VERSION 5.8 ;
BUSBITCHARS "[]" ;
DIVIDERCHAR "/" ;
UNITS
    DATABASE MICRONS 1000 ;
END UNITS

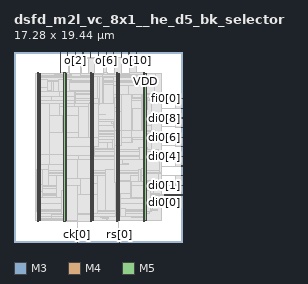
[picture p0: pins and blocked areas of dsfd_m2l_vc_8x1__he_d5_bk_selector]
MACRO dsfd_m2l_vc_8x1__he_d5_bk_selector
  FOREIGN dsfd_m2l_vc_8x1__he_d5_bk_selector 0 0 ;
  CLASS BLOCK ;
  SIZE 17.28 BY 19.44 ;
  PIN ck[0]
    DIRECTION INPUT ;
    USE SIGNAL ;
    PORT
      LAYER M3 ;
        RECT  6.48 0 6.498 0.144 ;
    END
    PORT
      LAYER M3 ;
        RECT  6.48 0.108 6.498 0.173 ;
    END
  END ck[0]
  PIN di0[0]
    DIRECTION INPUT ;
    USE SIGNAL ;
    PORT
      LAYER M4 ;
        RECT  17.088 4.8 17.28 4.824 ;
    END
    PORT
      LAYER M4 ;
        RECT  15.397 4.8 17.1 4.824 ;
    END
  END di0[0]
  PIN di0[1]
    DIRECTION INPUT ;
    USE SIGNAL ;
    PORT
      LAYER M4 ;
        RECT  17.088 5.808 17.28 5.832 ;
    END
  END di0[1]
  PIN di0[2]
    DIRECTION INPUT ;
    USE SIGNAL ;
    PORT
      LAYER M4 ;
        RECT  17.088 6.768 17.28 6.792 ;
    END
  END di0[2]
  PIN di0[3]
    DIRECTION INPUT ;
    USE SIGNAL ;
    PORT
      LAYER M4 ;
        RECT  17.088 7.776 17.28 7.8 ;
    END
  END di0[3]
  PIN di0[4]
    DIRECTION INPUT ;
    USE SIGNAL ;
    PORT
      LAYER M4 ;
        RECT  17.088 8.736 17.28 8.76 ;
    END
  END di0[4]
  PIN di0[5]
    DIRECTION INPUT ;
    USE SIGNAL ;
    PORT
      LAYER M4 ;
        RECT  17.088 9.744 17.28 9.768 ;
    END
  END di0[5]
  PIN di0[6]
    DIRECTION INPUT ;
    USE SIGNAL ;
    PORT
      LAYER M4 ;
        RECT  17.088 10.704 17.28 10.728 ;
    END
  END di0[6]
  PIN di0[7]
    DIRECTION INPUT ;
    USE SIGNAL ;
    PORT
      LAYER M4 ;
        RECT  17.088 11.712 17.28 11.736 ;
    END
  END di0[7]
  PIN di0[8]
    DIRECTION INPUT ;
    USE SIGNAL ;
    PORT
      LAYER M4 ;
        RECT  17.088 12.672 17.28 12.696 ;
    END
  END di0[8]
  PIN di0[9]
    DIRECTION INPUT ;
    USE SIGNAL ;
    PORT
      LAYER M4 ;
        RECT  17.088 13.68 17.28 13.704 ;
    END
  END di0[9]
  PIN fi0[0]
    DIRECTION INPUT ;
    USE SIGNAL ;
    PORT
      LAYER M4 ;
        RECT  17.088 14.64 17.28 14.664 ;
    END
  END fi0[0]
  PIN o[0]
    DIRECTION OUTPUT ;
    USE SIGNAL ;
    PORT
      LAYER M3 ;
        RECT  4.716 19.296 4.734 19.44 ;
    END
    PORT
      LAYER M3 ;
        RECT  4.716 17.297 4.734 19.308 ;
    END
  END o[0]
  PIN o[10]
    DIRECTION OUTPUT ;
    USE SIGNAL ;
    PORT
      LAYER M3 ;
        RECT  12.564 19.296 12.582 19.44 ;
    END
    PORT
      LAYER M3 ;
        RECT  12.564 18.845 12.582 19.308 ;
    END
  END o[10]
  PIN o[1]
    DIRECTION OUTPUT ;
    USE SIGNAL ;
    PORT
      LAYER M5 ;
        RECT  5.472 19.248 5.496 19.44 ;
    END
    PORT
      LAYER M5 ;
        RECT  5.472 18.805 5.496 19.28 ;
    END
  END o[1]
  PIN o[2]
    DIRECTION OUTPUT ;
    USE SIGNAL ;
    PORT
      LAYER M3 ;
        RECT  6.264 19.296 6.282 19.44 ;
    END
    PORT
      LAYER M3 ;
        RECT  6.264 18.845 6.282 19.308 ;
    END
  END o[2]
  PIN o[3]
    DIRECTION OUTPUT ;
    USE SIGNAL ;
    PORT
      LAYER M5 ;
        RECT  7.056 19.248 7.08 19.44 ;
    END
    PORT
      LAYER M5 ;
        RECT  7.056 18.805 7.08 19.28 ;
    END
  END o[3]
  PIN o[4]
    DIRECTION OUTPUT ;
    USE SIGNAL ;
    PORT
      LAYER M3 ;
        RECT  7.848 19.296 7.866 19.44 ;
    END
    PORT
      LAYER M3 ;
        RECT  7.848 18.845 7.866 19.308 ;
    END
  END o[4]
  PIN o[5]
    DIRECTION OUTPUT ;
    USE SIGNAL ;
    PORT
      LAYER M5 ;
        RECT  8.64 19.248 8.664 19.44 ;
    END
    PORT
      LAYER M5 ;
        RECT  8.64 18.805 8.664 19.28 ;
    END
  END o[5]
  PIN o[6]
    DIRECTION OUTPUT ;
    USE SIGNAL ;
    PORT
      LAYER M3 ;
        RECT  9.432 19.296 9.45 19.44 ;
    END
    PORT
      LAYER M3 ;
        RECT  9.432 18.845 9.45 19.308 ;
    END
  END o[6]
  PIN o[7]
    DIRECTION OUTPUT ;
    USE SIGNAL ;
    PORT
      LAYER M5 ;
        RECT  10.176 19.248 10.2 19.44 ;
    END
    PORT
      LAYER M5 ;
        RECT  10.176 18.805 10.2 19.28 ;
    END
  END o[7]
  PIN o[8]
    DIRECTION OUTPUT ;
    USE SIGNAL ;
    PORT
      LAYER M3 ;
        RECT  10.98 19.296 10.998 19.44 ;
    END
    PORT
      LAYER M3 ;
        RECT  10.98 18.845 10.998 19.308 ;
    END
  END o[8]
  PIN o[9]
    DIRECTION OUTPUT ;
    USE SIGNAL ;
    PORT
      LAYER M5 ;
        RECT  11.76 19.248 11.784 19.44 ;
    END
    PORT
      LAYER M5 ;
        RECT  11.76 18.805 11.784 19.28 ;
    END
  END o[9]
  PIN rs[0]
    DIRECTION INPUT ;
    USE SIGNAL ;
    PORT
      LAYER M5 ;
        RECT  10.8 0 10.824 0.192 ;
    END
    PORT
      LAYER M5 ;
        RECT  10.8 0.144 10.824 0.227 ;
    END
  END rs[0]
  PIN VDD
    DIRECTION INOUT ;
    USE POWER ;
    PORT
      LAYER M5 ;
        RECT  13.392 2.151 13.512 17.289 ;
        RECT  10.692 2.151 10.812 17.289 ;
        RECT  7.992 2.151 8.112 17.289 ;
        RECT  5.292 2.151 5.412 17.289 ;
        RECT  2.592 2.151 2.712 17.289 ;
    END
  END VDD
  PIN VSS
    DIRECTION INOUT ;
    USE GROUND ;
    PORT
      LAYER M5 ;
        RECT  13.2 2.137 13.32 17.303 ;
        RECT  10.5 2.137 10.62 17.303 ;
        RECT  7.8 2.137 7.92 17.303 ;
        RECT  5.1 2.137 5.22 17.303 ;
        RECT  2.4 2.137 2.52 17.303 ;
    END
  END VSS
  # OT_OBS_CLOSED layer=M5 d_um=1.536 added=29
  OBS
    LAYER RVTN ;
     RECT  2.16 2.16 15.12 2.295 ;
     RECT  2.16 2.565 15.12 2.835 ;
     RECT  2.16 3.105 15.12 3.375 ;
     RECT  2.16 3.645 15.12 3.915 ;
     RECT  2.16 4.185 15.12 4.455 ;
     RECT  2.16 4.725 15.12 4.995 ;
     RECT  2.16 5.265 15.12 5.535 ;
     RECT  2.16 5.805 15.12 6.075 ;
     RECT  2.16 6.345 15.12 6.615 ;
     RECT  2.16 6.885 15.12 7.155 ;
     RECT  2.16 7.425 15.12 7.695 ;
     RECT  2.16 7.965 15.12 8.235 ;
     RECT  2.16 8.505 15.12 8.775 ;
     RECT  2.16 9.045 15.12 9.315 ;
     RECT  2.16 9.585 15.12 9.855 ;
     RECT  2.16 10.125 15.12 10.395 ;
     RECT  2.16 10.665 15.12 10.935 ;
     RECT  2.16 11.205 15.12 11.475 ;
     RECT  2.16 11.745 15.12 12.015 ;
     RECT  2.16 12.285 15.12 12.555 ;
     RECT  2.16 12.825 15.12 13.095 ;
     RECT  2.16 13.365 15.12 13.635 ;
     RECT  2.16 13.905 15.12 14.175 ;
     RECT  2.16 14.445 15.12 14.715 ;
     RECT  2.16 14.985 15.12 15.255 ;
     RECT  2.16 15.525 15.12 15.795 ;
     RECT  2.16 16.065 15.12 16.335 ;
     RECT  2.16 16.605 15.12 16.875 ;
     RECT  2.16 17.145 15.12 17.28 ;
    LAYER RVTP ;
     RECT  2.16 2.295 15.12 2.565 ;
     RECT  2.16 2.835 15.12 3.105 ;
     RECT  2.16 3.375 15.12 3.645 ;
     RECT  2.16 3.915 15.12 4.185 ;
     RECT  2.16 4.455 15.12 4.725 ;
     RECT  2.16 4.995 15.12 5.265 ;
     RECT  2.16 5.535 15.12 5.805 ;
     RECT  2.16 6.075 15.12 6.345 ;
     RECT  2.16 6.615 15.12 6.885 ;
     RECT  2.16 7.155 15.12 7.425 ;
     RECT  2.16 7.695 15.12 7.965 ;
     RECT  2.16 8.235 15.12 8.505 ;
     RECT  2.16 8.775 15.12 9.045 ;
     RECT  2.16 9.315 15.12 9.585 ;
     RECT  2.16 9.855 15.12 10.125 ;
     RECT  2.16 10.395 15.12 10.665 ;
     RECT  2.16 10.935 15.12 11.205 ;
     RECT  2.16 11.475 15.12 11.745 ;
     RECT  2.16 12.015 15.12 12.285 ;
     RECT  2.16 12.555 15.12 12.825 ;
     RECT  2.16 13.095 15.12 13.365 ;
     RECT  2.16 13.635 15.12 13.905 ;
     RECT  2.16 14.175 15.12 14.445 ;
     RECT  2.16 14.715 15.12 14.985 ;
     RECT  2.16 15.255 15.12 15.525 ;
     RECT  2.16 15.795 15.12 16.065 ;
     RECT  2.16 16.335 15.12 16.605 ;
     RECT  2.16 16.875 15.12 17.145 ;
    LAYER M1 ;
     RECT  2.16 2.151 15.12 17.289 ;
    LAYER M2 ;
     RECT  6.259 18.81 6.863 18.828 ;
     RECT  7.663 18.774 7.871 18.792 ;
     RECT  2.16 2.151 9.427 17.289 ;
     RECT  9.427 2.151 9.527 17.334 ;
     RECT  9.527 2.151 15.12 17.289 ;
     RECT  15.12 4.77 15.431 4.788 ;
     RECT  15.12 6.048 15.431 6.066 ;
     RECT  15.12 6.822 16.547 6.84 ;
     RECT  15.12 7.704 16.547 7.722 ;
     RECT  15.12 8.784 16.547 8.802 ;
     RECT  15.12 9.9 16.547 9.918 ;
     RECT  15.12 10.872 16.547 10.89 ;
     RECT  15.12 11.79 16.547 11.808 ;
     RECT  15.12 12.87 16.547 12.888 ;
     RECT  15.12 13.644 16.547 13.662 ;
    LAYER M3 ;
     RECT  10.656 0.187 10.674 2.143 ;
     RECT  2.415 2.143 2.505 2.191 ;
     RECT  5.115 2.143 5.205 2.191 ;
     RECT  2.415 2.191 2.898 2.263 ;
     RECT  2.415 2.263 3.366 2.335 ;
     RECT  2.415 2.335 3.618 2.347 ;
     RECT  4.5 2.191 5.205 2.347 ;
     RECT  2.415 2.347 5.205 2.371 ;
     RECT  2.415 2.371 5.274 2.413 ;
     RECT  7.815 2.143 7.905 2.413 ;
     RECT  10.515 2.143 10.674 2.413 ;
     RECT  13.215 2.143 13.305 2.413 ;
     RECT  13.215 2.413 13.497 2.461 ;
     RECT  9.036 2.371 9.702 2.497 ;
     RECT  8.82 2.497 9.702 2.587 ;
     RECT  10.515 2.413 10.797 2.587 ;
     RECT  11.988 2.461 13.497 2.587 ;
     RECT  2.415 2.413 5.397 2.605 ;
     RECT  6.228 2.569 6.246 2.605 ;
     RECT  2.415 2.605 6.75 2.641 ;
     RECT  7.815 2.413 8.097 2.641 ;
     RECT  8.82 2.587 13.497 2.641 ;
     RECT  2.415 2.641 13.497 2.911 ;
     RECT  2.415 2.911 13.842 3.145 ;
     RECT  2.34 3.145 14.022 3.181 ;
     RECT  2.34 3.181 14.67 3.335 ;
     RECT  2.34 3.335 14.13 3.983 ;
     RECT  2.415 3.983 14.13 4.531 ;
     RECT  2.415 4.531 14.85 4.765 ;
     RECT  2.415 4.765 15.426 4.829 ;
     RECT  2.415 4.829 14.85 4.955 ;
     RECT  2.415 4.955 14.238 5.461 ;
     RECT  2.412 5.461 14.238 5.701 ;
     RECT  2.412 5.701 14.742 5.803 ;
     RECT  2.412 5.803 15.426 6.071 ;
     RECT  2.412 6.071 14.742 6.235 ;
     RECT  2.376 6.235 14.742 6.275 ;
     RECT  16.524 6.763 16.542 6.845 ;
     RECT  2.415 6.275 14.742 6.961 ;
     RECT  2.415 6.961 14.994 7.079 ;
     RECT  2.415 7.079 14.85 7.339 ;
     RECT  2.412 7.339 14.85 7.357 ;
     RECT  16.524 7.699 16.542 7.805 ;
     RECT  2.376 7.357 14.85 8.429 ;
     RECT  2.415 8.429 14.85 8.707 ;
     RECT  2.415 8.707 14.886 8.807 ;
     RECT  16.524 8.731 16.542 8.807 ;
     RECT  2.415 8.807 14.778 9.259 ;
     RECT  2.376 9.259 14.778 9.509 ;
     RECT  16.524 9.739 16.542 9.923 ;
     RECT  2.415 9.509 14.094 10.471 ;
     RECT  2.415 10.471 14.346 10.831 ;
     RECT  16.524 10.699 16.542 10.895 ;
     RECT  2.415 10.831 14.526 11.011 ;
     RECT  2.415 11.011 14.994 11.129 ;
     RECT  2.415 11.129 14.562 11.357 ;
     RECT  2.415 11.357 14.526 11.399 ;
     RECT  2.415 11.399 14.418 11.435 ;
     RECT  2.415 11.435 14.094 11.443 ;
     RECT  16.524 11.707 16.542 11.813 ;
     RECT  2.376 11.443 14.094 11.939 ;
     RECT  2.415 11.939 14.094 12.361 ;
     RECT  2.415 12.361 14.13 12.515 ;
     RECT  16.524 12.667 16.542 12.893 ;
     RECT  16.524 13.639 16.542 13.709 ;
     RECT  2.415 12.515 14.094 14.521 ;
     RECT  2.415 14.521 14.778 14.675 ;
     RECT  2.415 14.675 14.526 15.061 ;
     RECT  2.376 15.061 14.526 15.179 ;
     RECT  2.376 15.179 14.418 15.215 ;
     RECT  2.376 15.215 14.346 16.339 ;
     RECT  2.376 16.339 14.526 16.375 ;
     RECT  2.376 16.375 14.634 16.529 ;
     RECT  2.415 16.529 14.526 16.799 ;
     RECT  2.415 16.799 13.497 16.943 ;
     RECT  2.415 16.943 5.922 17.027 ;
     RECT  9.108 16.943 13.497 17.027 ;
     RECT  3.348 17.027 5.922 17.069 ;
     RECT  6.84 16.943 8.298 17.069 ;
     RECT  9.108 17.027 13.305 17.069 ;
     RECT  14.436 16.799 14.526 17.069 ;
     RECT  4.176 17.069 5.922 17.105 ;
     RECT  10.332 17.069 13.305 17.105 ;
     RECT  14.436 17.069 14.454 17.105 ;
     RECT  4.284 17.105 5.634 17.141 ;
     RECT  6.84 17.069 8.19 17.213 ;
     RECT  2.415 17.027 2.505 17.297 ;
     RECT  4.716 17.141 5.634 17.297 ;
     RECT  11.844 17.105 13.305 17.297 ;
     RECT  9.108 17.069 9.522 17.339 ;
     RECT  7.668 17.213 8.19 18.797 ;
     RECT  5.616 17.297 5.634 18.805 ;
     RECT  6.84 17.213 6.858 18.805 ;
     RECT  5.616 18.805 6.858 18.833 ;
     RECT  5.616 18.833 6.282 18.845 ;
     RECT  7.848 18.797 8.19 18.845 ;
     RECT  9.108 17.339 9.45 18.845 ;
     RECT  10.332 17.105 10.998 18.845 ;
     RECT  11.844 17.297 12.582 18.845 ;
    LAYER M4 ;
     RECT  2.293 7.344 2.365 7.368 ;
     RECT  2.293 6.24 2.401 6.264 ;
     RECT  2.293 3.936 2.408 3.96 ;
     RECT  2.401 5.472 2.408 6.264 ;
     RECT  2.365 7.344 2.408 7.944 ;
     RECT  2.365 9.264 2.408 9.288 ;
     RECT  2.365 16.032 2.408 16.056 ;
     RECT  2.408 2.148 2.512 17.292 ;
     RECT  2.512 2.4 2.704 17.022 ;
     RECT  2.704 4.512 2.915 9.288 ;
     RECT  2.704 15.456 3.443 16.584 ;
     RECT  2.704 13.872 3.449 14.424 ;
     RECT  2.915 5.808 3.491 9.288 ;
     RECT  2.704 2.4 3.589 2.424 ;
     RECT  3.491 7.92 3.635 9.192 ;
     RECT  3.449 14.208 3.797 14.424 ;
     RECT  3.443 15.456 3.797 16.392 ;
     RECT  3.589 2.352 3.805 2.424 ;
     RECT  3.805 2.352 3.845 2.808 ;
     RECT  3.797 14.208 3.875 16.392 ;
     RECT  3.875 14.352 4.061 16.392 ;
     RECT  3.913 13.008 4.097 13.128 ;
     RECT  4.097 13.008 4.133 13.032 ;
     RECT  2.915 4.512 4.381 4.536 ;
     RECT  3.491 5.808 4.381 6.84 ;
     RECT  4.061 14.4 4.525 16.392 ;
     RECT  2.704 11.376 4.645 11.976 ;
     RECT  3.635 8.208 4.741 9.192 ;
     RECT  4.645 11.376 4.777 12.936 ;
     RECT  3.845 2.784 4.885 2.808 ;
     RECT  4.885 2.784 5.108 2.904 ;
     RECT  4.381 4.512 5.108 6.84 ;
     RECT  4.741 8.16 5.108 9.192 ;
     RECT  4.777 10.944 5.108 12.936 ;
     RECT  4.525 14.4 5.108 16.584 ;
     RECT  5.108 2.148 5.212 17.292 ;
     RECT  5.212 2.418 5.404 17.022 ;
     RECT  5.461 18.816 5.645 18.84 ;
     RECT  5.404 2.784 5.681 2.808 ;
     RECT  5.404 14.112 5.681 16.584 ;
     RECT  5.681 16.56 5.933 16.584 ;
     RECT  5.681 14.112 6.329 15.48 ;
     RECT  5.404 5.136 6.397 11.256 ;
     RECT  5.404 12.24 6.397 13.128 ;
     RECT  6.428 0.144 6.515 0.168 ;
     RECT  6.397 5.136 6.541 13.128 ;
     RECT  6.329 14.112 6.541 14.136 ;
     RECT  6.541 5.136 6.721 14.136 ;
     RECT  6.721 2.832 6.805 2.856 ;
     RECT  6.721 4.848 7.693 14.136 ;
     RECT  6.805 2.832 7.765 3.576 ;
     RECT  7.693 4.848 7.765 14.232 ;
     RECT  6.329 15.36 7.801 15.48 ;
     RECT  7.765 2.832 7.808 14.232 ;
     RECT  7.801 15.36 7.808 15.528 ;
     RECT  6.829 17.04 7.808 17.064 ;
     RECT  7.808 2.148 7.912 17.292 ;
     RECT  7.912 2.418 8.104 17.022 ;
     RECT  8.104 8.832 8.243 10.584 ;
     RECT  8.104 11.664 8.243 17.022 ;
     RECT  8.243 12.24 8.245 17.022 ;
     RECT  8.243 9.6 8.281 10.584 ;
     RECT  8.104 2.88 8.531 6.792 ;
     RECT  8.245 12.24 8.597 13.08 ;
     RECT  8.245 14.112 8.705 17.022 ;
     RECT  8.705 14.208 9.061 17.022 ;
     RECT  9.061 14.208 9.107 17.112 ;
     RECT  7.045 18.816 9.137 18.84 ;
     RECT  9.107 17.088 9.245 17.112 ;
     RECT  8.597 13.056 9.317 13.08 ;
     RECT  8.531 3.264 9.385 6.792 ;
     RECT  8.281 9.6 9.565 10.2 ;
     RECT  9.925 12.288 9.961 12.312 ;
     RECT  9.565 9.552 10.069 10.2 ;
     RECT  9.961 12.144 10.141 12.312 ;
     RECT  9.107 14.208 10.172 16.104 ;
     RECT  10.141 12.096 10.177 12.312 ;
     RECT  10.172 14.208 10.241 16.392 ;
     RECT  9.385 3.264 10.357 7.368 ;
     RECT  9.097 8.448 10.357 8.472 ;
     RECT  10.165 18.816 10.361 18.84 ;
     RECT  10.357 2.592 10.508 8.472 ;
     RECT  10.069 9.552 10.508 10.44 ;
     RECT  10.177 11.76 10.508 12.312 ;
     RECT  10.241 13.68 10.508 16.392 ;
     RECT  10.508 2.148 10.612 17.292 ;
     RECT  10.612 2.418 10.804 17.022 ;
     RECT  10.645 0.192 10.835 0.216 ;
     RECT  10.804 2.592 10.931 6.312 ;
     RECT  10.804 9.888 10.979 16.008 ;
     RECT  10.804 7.968 11.081 8.472 ;
     RECT  10.931 4.416 11.117 6.312 ;
     RECT  10.931 2.592 11.441 3.384 ;
     RECT  11.081 7.968 11.765 7.992 ;
     RECT  11.749 18.816 11.873 18.84 ;
     RECT  11.117 4.512 11.905 6.312 ;
     RECT  11.905 4.512 11.945 6.84 ;
     RECT  11.945 4.512 11.987 4.584 ;
     RECT  11.441 2.592 12.017 2.616 ;
     RECT  10.979 10.224 12.053 16.008 ;
     RECT  12.053 14.736 12.085 16.008 ;
     RECT  12.053 10.224 12.089 13.656 ;
     RECT  11.945 5.712 12.733 6.84 ;
     RECT  12.733 8.448 12.805 8.472 ;
     RECT  12.769 9.6 12.805 9.624 ;
     RECT  11.987 4.56 12.913 4.584 ;
     RECT  12.733 5.712 12.913 7.464 ;
     RECT  12.085 14.736 13.057 16.056 ;
     RECT  12.089 10.752 13.093 13.656 ;
     RECT  13.057 14.64 13.093 16.056 ;
     RECT  13.093 10.752 13.165 16.056 ;
     RECT  12.913 4.56 13.208 7.464 ;
     RECT  12.805 8.448 13.208 9.624 ;
     RECT  13.165 10.752 13.208 16.44 ;
     RECT  13.208 2.148 13.312 17.292 ;
     RECT  13.312 2.418 13.504 17.022 ;
     RECT  13.504 13.104 13.565 14.76 ;
     RECT  13.504 4.512 13.601 6.84 ;
     RECT  13.504 16.032 13.637 16.056 ;
     RECT  13.504 9.6 13.673 9.624 ;
     RECT  13.504 8.448 13.709 8.472 ;
     RECT  13.565 13.584 13.709 14.76 ;
     RECT  13.709 14.496 13.853 14.76 ;
     RECT  13.853 14.496 13.961 14.664 ;
     RECT  13.601 4.512 14.003 6.072 ;
     RECT  13.504 3.168 14.044 3.192 ;
     RECT  14.003 4.512 14.044 4.536 ;
     RECT  14.003 6.048 14.069 6.072 ;
     RECT  13.504 11.328 14.573 11.352 ;
     RECT  15.397 5.808 16.513 5.832 ;
     RECT  13.961 14.64 16.513 14.664 ;
     RECT  16.513 5.808 17.1 6.792 ;
     RECT  16.513 7.776 17.1 8.76 ;
     RECT  16.513 9.744 17.1 10.728 ;
     RECT  16.513 11.712 17.1 12.696 ;
     RECT  16.513 13.68 17.1 14.664 ;
    LAYER M5 ;
     RECT  2.4 2.137 2.52 2.151 ;
     RECT  5.1 2.137 5.22 2.151 ;
     RECT  7.8 2.137 7.92 2.151 ;
     RECT  10.5 2.137 10.62 2.151 ;
     RECT  13.2 2.137 13.32 2.151 ;
     RECT  5.1 2.151 5.412 2.773 ;
     RECT  6.48 0.133 6.504 2.821 ;
     RECT  7.8 2.151 8.112 2.821 ;
     RECT  6.48 2.821 8.112 2.869 ;
     RECT  13.2 2.151 13.512 3.157 ;
     RECT  2.4 2.151 2.712 3.925 ;
     RECT  10.5 2.151 10.812 3.925 ;
     RECT  11.952 4.501 11.976 4.549 ;
     RECT  6.48 2.869 8.52 4.883 ;
     RECT  10.5 3.925 10.92 4.931 ;
     RECT  2.304 3.925 2.712 5.125 ;
     RECT  4.896 2.773 5.412 5.219 ;
     RECT  13.2 3.157 13.992 5.219 ;
     RECT  11.952 4.549 12.072 5.747 ;
     RECT  5.1 5.219 5.412 5.797 ;
     RECT  6.48 4.883 6.792 5.797 ;
     RECT  2.304 5.125 2.904 5.843 ;
     RECT  7.8 4.883 8.52 6.035 ;
     RECT  10.5 4.931 10.812 6.085 ;
     RECT  11.952 5.747 11.976 6.227 ;
     RECT  5.1 5.797 6.792 6.515 ;
     RECT  13.2 5.219 13.512 6.805 ;
     RECT  2.304 5.843 2.712 7.379 ;
     RECT  2.4 7.379 2.712 7.381 ;
     RECT  13.056 6.805 13.512 7.475 ;
     RECT  2.4 7.381 3.48 7.909 ;
     RECT  5.1 6.515 6.504 8.485 ;
     RECT  5.1 8.485 6.6 8.821 ;
     RECT  7.8 6.035 8.112 8.821 ;
     RECT  2.4 7.909 3.624 8.965 ;
     RECT  5.1 8.821 8.232 9.781 ;
     RECT  10.272 6.085 10.812 9.877 ;
     RECT  5.1 9.781 8.664 10.739 ;
     RECT  5.1 10.739 6.648 11.221 ;
     RECT  10.272 9.877 10.968 11.365 ;
     RECT  12 10.645 12.024 11.411 ;
     RECT  4.944 11.221 6.648 12.901 ;
     RECT  10.272 11.365 11.016 13.379 ;
     RECT  10.272 13.379 10.812 13.715 ;
     RECT  4.656 12.901 6.648 13.859 ;
     RECT  7.632 10.739 8.664 14.147 ;
     RECT  2.4 8.965 3.672 14.197 ;
     RECT  4.656 13.859 6.216 14.197 ;
     RECT  2.4 14.197 6.216 14.435 ;
     RECT  13.2 7.475 13.512 14.485 ;
     RECT  7.8 14.147 8.664 14.675 ;
     RECT  13.104 14.485 13.512 14.771 ;
     RECT  10.5 13.715 10.812 14.773 ;
     RECT  3.84 14.435 6.216 14.867 ;
     RECT  10.224 14.773 10.812 15.061 ;
     RECT  4.656 14.867 6.168 15.395 ;
     RECT  4.656 15.395 5.412 15.443 ;
     RECT  2.4 14.435 2.712 15.829 ;
     RECT  10.224 15.061 11.688 16.019 ;
     RECT  10.224 16.019 10.812 16.403 ;
     RECT  2.4 15.829 3.432 16.595 ;
     RECT  7.8 14.675 8.52 16.885 ;
     RECT  7.8 16.885 9.096 17.123 ;
     RECT  2.4 16.595 2.712 17.289 ;
     RECT  5.1 15.443 5.412 17.289 ;
     RECT  7.8 17.123 8.112 17.289 ;
     RECT  10.5 16.403 10.812 17.289 ;
     RECT  13.2 14.771 13.512 17.289 ;
     RECT  2.4 17.289 2.52 17.303 ;
     RECT  5.1 17.289 5.22 17.303 ;
     RECT  7.8 17.289 7.92 17.303 ;
     RECT  10.5 17.289 10.62 17.303 ;
     RECT  13.2 17.289 13.32 17.303 ;
     RECT  5.22 2.137 6.48 2.151 ;
     RECT  6.504 2.137 7.8 2.821 ;
     RECT  5.412 2.151 6.48 5.797 ;
     RECT  10.92 4.501 11.952 4.931 ;
     RECT  11.976 4.501 13.2 4.549 ;
     RECT  12.072 4.549 13.2 5.747 ;
     RECT  6.792 4.883 7.8 6.515 ;
     RECT  10.812 4.931 11.952 6.227 ;
     RECT  11.976 5.747 13.2 6.227 ;
     RECT  13.056 6.227 13.2 6.805 ;
     RECT  6.504 6.515 7.8 8.485 ;
     RECT  3.624 7.909 5.1 8.965 ;
     RECT  6.6 8.485 7.8 8.821 ;
     RECT  3.672 8.965 5.1 11.221 ;
     RECT  10.968 10.645 12 11.365 ;
     RECT  12.024 10.645 13.2 11.411 ;
     RECT  6.648 10.739 7.632 13.859 ;
     RECT  3.672 11.221 4.944 12.901 ;
     RECT  11.016 11.365 12 11.411 ;
     RECT  3.672 12.901 4.656 14.197 ;
     RECT  10.272 13.715 10.5 14.773 ;
     RECT  6.216 13.859 7.632 14.147 ;
     RECT  2.712 14.435 3.84 14.867 ;
     RECT  13.104 14.771 13.2 15.061 ;
     RECT  2.712 14.867 4.656 15.443 ;
     RECT  11.688 15.061 13.2 16.019 ;
     RECT  2.712 15.443 3.432 15.829 ;
     RECT  10.224 16.403 10.5 16.885 ;
     RECT  9.096 16.885 10.5 17.123 ;
  END
END dsfd_m2l_vc_8x1__he_d5_bk_selector
END LIBRARY
